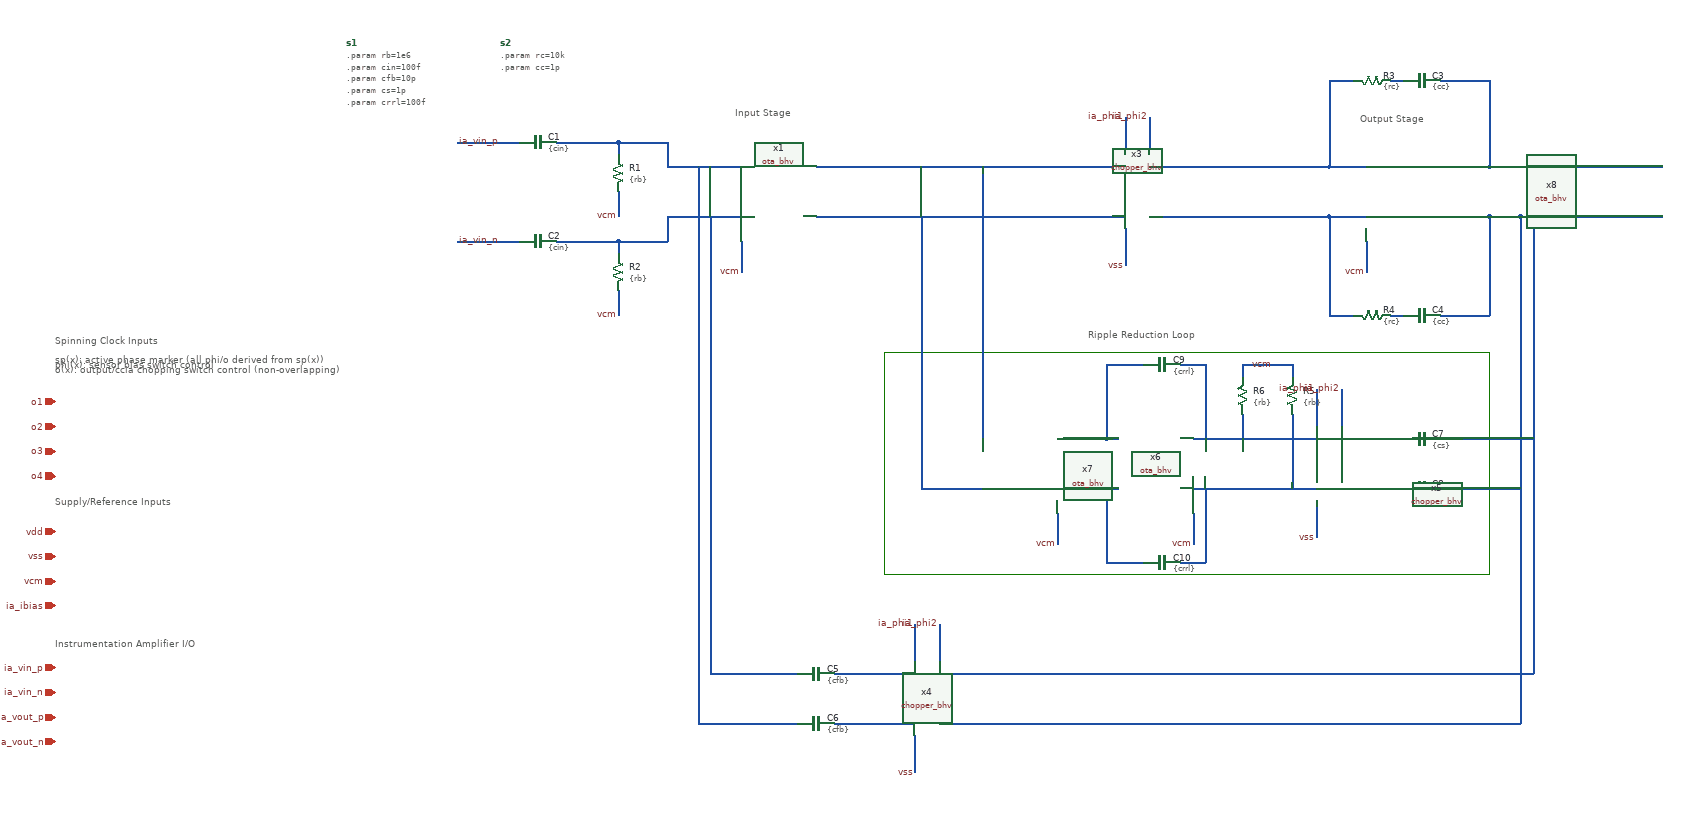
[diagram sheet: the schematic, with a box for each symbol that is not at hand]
v {xschem version=3.4.8RC file_version=1.3}
G {}
K {}
V {}
S {}
F {}
E {}
L 4 1340 -780 2320 -780 {}
L 4 1340 -780 1340 -420 {}
L 4 1340 -420 1900 -420 {}
L 4 1900 -420 2320 -420 {}
L 4 2320 -780 2320 -420 {}
T {Spinning Clock Inputs} 0 -810 0 0 0.4 0.4 {}
T {sp(x): active phase marker (all phi/o derived from sp(x))
phi(x): sensor bias switch control
o(x): output/ccia chopping switch control (non-overlapping)
} 0 -780 0 0 0.2 0.2 {}
T {Supply/Reference Inputs} 0 -550 0 0 0.4 0.4 {}
T {Instrumentation Amplifier I/O} 0 -320 0 0 0.4 0.4 {}
T {Ripple Reduction Loop} 1670 -820 0 0 0.4 0.4 {}
T {Input Stage} 1100 -1180 0 0 0.4 0.4 {}
T {Output Stage} 2110 -1170 0 0 0.4 0.4 {}
N 910 -1040 910 -1020 {lab=vcm}
N 810 -1120 910 -1120 {lab=#net1}
N 910 -1120 910 -1100 {lab=#net1}
N 910 -1020 910 -1000 {lab=vcm}
N 910 -880 910 -860 {lab=vcm}
N 810 -960 910 -960 {lab=#net2}
N 910 -960 910 -940 {lab=#net2}
N 910 -860 910 -840 {lab=vcm}
N 650 -1120 750 -1120 {lab=ia_vin_p}
N 650 -960 750 -960 {lab=ia_vin_n}
N 910 -960 990 -960 {lab=#net2}
N 990 -1000 990 -960 {lab=#net2}
N 990 -1000 1110 -1000 {lab=#net2}
N 910 -1120 990 -1120 {lab=#net1}
N 990 -1120 990 -1080 {lab=#net1}
N 990 -1080 1110 -1080 {lab=#net1}
N 2060 -1080 2120 -1080 {lab=#net3}
N 2060 -1220 2060 -1080 {lab=#net3}
N 2060 -1220 2100 -1220 {lab=#net3}
N 2160 -1220 2180 -1220 {lab=#net4}
N 2240 -1220 2320 -1220 {lab=#net5}
N 2320 -1220 2320 -1080 {lab=#net5}
N 2240 -1080 2320 -1080 {lab=#net5}
N 2240 -1000 2320 -1000 {lab=#net6}
N 2320 -1000 2320 -840 {lab=#net6}
N 2240 -840 2320 -840 {lab=#net6}
N 2160 -840 2180 -840 {lab=#net7}
N 2060 -840 2100 -840 {lab=#net8}
N 2060 -1000 2060 -840 {lab=#net8}
N 1230 -1000 1350 -1000 {lab=#net9}
N 2060 -1000 2120 -1000 {lab=#net8}
N 1230 -1080 1350 -1080 {lab=#net10}
N 1690 -1000 1730 -1000 {lab=#net9}
N 1690 -1080 1730 -1080 {lab=#net10}
N 2000 -1080 2060 -1080 {lab=#net3}
N 2000 -1000 2060 -1000 {lab=#net8}
N 1260 -180 1390 -180 {lab=#net11}
N 1260 -260 1390 -260 {lab=#net12}
N 1430 -180 1800 -180 {lab=#net6}
N 2370 -1000 2370 -570 {lab=#net6}
N 2320 -1000 2370 -1000 {lab=#net6}
N 1070 -260 1200 -260 {lab=#net2}
N 1060 -260 1070 -260 {lab=#net2}
N 1060 -1000 1060 -650 {lab=#net2}
N 1040 -1080 1040 -570 {lab=#net1}
N 1040 -180 1200 -180 {lab=#net1}
N 1110 -960 1110 -910 {lab=vcm}
N 2120 -960 2120 -910 {lab=vcm}
N 1040 -570 1040 -290 {lab=#net1}
N 1060 -650 1060 -370 {lab=#net2}
N 2390 -1080 2390 -370 {lab=#net5}
N 2370 -570 2370 -290 {lab=#net6}
N 2320 -1080 2390 -1080 {lab=#net5}
N 1430 -260 1820 -260 {lab=#net5}
N 1350 -1080 1690 -1080 {lab=#net10}
N 1350 -1000 1690 -1000 {lab=#net9}
N 1770 -1080 2000 -1080 {lab=#net3}
N 1770 -1000 2000 -1000 {lab=#net8}
N 1820 -260 2390 -260 {lab=#net5}
N 1800 -180 2370 -180 {lab=#net6}
N 2240 -640 2390 -640 {lab=#net5}
N 2240 -560 2370 -560 {lab=#net6}
N 2080 -640 2180 -640 {lab=#net13}
N 2080 -560 2180 -560 {lab=#net14}
N 1920 -680 1920 -640 {lab=#net15}
N 1840 -560 2040 -560 {lab=#net16}
N 1840 -640 2040 -640 {lab=#net15}
N 2000 -680 2000 -560 {lab=#net16}
N 1920 -760 1920 -740 {lab=vcm}
N 1920 -760 2000 -760 {lab=vcm}
N 2000 -760 2000 -740 {lab=vcm}
N 1860 -760 1860 -640 {lab=#net15}
N 1820 -760 1860 -760 {lab=#net15}
N 1700 -760 1700 -640 {lab=#net17}
N 1700 -640 1720 -640 {lab=#net17}
N 1700 -760 1760 -760 {lab=#net17}
N 1860 -560 1860 -440 {lab=#net16}
N 1820 -440 1860 -440 {lab=#net16}
N 1700 -560 1700 -440 {lab=#net18}
N 1700 -440 1760 -440 {lab=#net18}
N 1700 -560 1720 -560 {lab=#net18}
N 1620 -640 1700 -640 {lab=#net17}
N 1620 -560 1700 -560 {lab=#net18}
N 1500 -1080 1500 -660 {lab=#net10}
N 1400 -560 1500 -560 {lab=#net9}
N 1400 -1000 1400 -580 {lab=#net9}
N 1400 -580 1400 -560 {lab=#net9}
N 1500 -660 1500 -640 {lab=#net10}
N 2370 -1000 2600 -1000 {lab=#net6}
N 2390 -1080 2600 -1080 {lab=#net5}
N 1730 -1140 1730 -1100 {lab=ia_phi1}
N 1730 -1160 1730 -1140 {lab=ia_phi1}
N 1770 -1140 1770 -1100 {lab=ia_phi2}
N 1770 -1160 1770 -1140 {lab=ia_phi2}
N 1730 -980 1730 -920 {lab=vss}
N 1040 -290 1040 -180 {lab=#net1}
N 1060 -370 1060 -260 {lab=#net2}
N 2370 -290 2370 -180 {lab=#net6}
N 2390 -370 2390 -260 {lab=#net5}
N 1390 -320 1390 -280 {lab=ia_phi1}
N 1390 -340 1390 -320 {lab=ia_phi1}
N 1430 -320 1430 -280 {lab=ia_phi2}
N 1430 -340 1430 -320 {lab=ia_phi2}
N 1390 -160 1390 -100 {lab=vss}
N 2040 -700 2040 -660 {lab=ia_phi1}
N 2040 -720 2040 -700 {lab=ia_phi1}
N 2080 -700 2080 -660 {lab=ia_phi2}
N 2080 -720 2080 -700 {lab=ia_phi2}
N 2040 -540 2040 -480 {lab=vss}
N 1620 -520 1620 -470 {lab=vcm}
N 1840 -520 1840 -470 {lab=vcm}
C {iopin.sym} 0 -700 0 0 {name=p13 lab=o1}
C {iopin.sym} 0 -660 0 0 {name=p14 lab=o2}
C {iopin.sym} 0 -620 0 0 {name=p15 lab=o3}
C {iopin.sym} 0 -580 0 0 {name=p16 lab=o4}
C {iopin.sym} 0 -490 0 0 {name=p20 lab=vdd}
C {iopin.sym} 0 -450 0 0 {name=p21 lab=vss}
C {iopin.sym} 0 -270 0 0 {name=p18 lab=ia_vin_p}
C {iopin.sym} 0 -230 0 0 {name=p19 lab=ia_vin_n}
C {iopin.sym} 0 -410 0 0 {name=p1 lab=vcm}
C {iopin.sym} 0 -370 0 0 {name=p2 lab=ia_ibias}
C {iopin.sym} 0 -190 0 0 {name=p3 lab=ia_vout_p}
C {iopin.sym} 0 -150 0 0 {name=p4 lab=ia_vout_n}
C {title.sym} 160 -40 0 0 {name=l1 author="alang"}
C {capa.sym} 780 -1120 1 0 {name=C1
m=1
value=\{cin\}
footprint=1206
device="ceramic capacitor"}
C {capa.sym} 780 -960 1 0 {name=C2
m=1
value=\{cin\}
footprint=1206
device="ceramic capacitor"}
C {res.sym} 910 -1070 0 0 {name=R1
value=\{rb\}
footprint=1206
device=resistor
m=1}
C {lab_wire.sym} 910 -1000 1 0 {name=p5 sig_type=std_logic lab=vcm}
C {res.sym} 910 -910 0 0 {name=R2
value=\{rb\}
footprint=1206
device=resistor
m=1}
C {lab_wire.sym} 910 -840 1 0 {name=p6 sig_type=std_logic lab=vcm}
C {capa.sym} 2210 -1220 1 0 {name=C3
m=1
value=\{cc\}
footprint=1206
device="ceramic capacitor"}
C {res.sym} 2130 -1220 1 0 {name=R3
value=\{rc\}
footprint=1206
device=resistor
m=1}
C {capa.sym} 2210 -840 1 0 {name=C4
m=1
value=\{cc\}
footprint=1206
device="ceramic capacitor"}
C {res.sym} 2130 -840 1 0 {name=R4
value=\{rc\}
footprint=1206
device=resistor
m=1}
C {chopper_bhv/chopper_bhv.sym} 1730 -980 0 0 {name=x3}
C {chopper_bhv/chopper_bhv.sym} 1390 -160 0 0 {name=x4}
C {capa.sym} 1230 -260 1 0 {name=C5
m=1
value=\{cfb\}
footprint=1206
device="ceramic capacitor"}
C {capa.sym} 1230 -180 1 0 {name=C6
m=1
value=\{cfb\}
footprint=1206
device="ceramic capacitor"}
C {lab_wire.sym} 1110 -910 1 0 {name=p7 sig_type=std_logic lab=vcm}
C {lab_wire.sym} 2120 -910 1 0 {name=p8 sig_type=std_logic lab=vcm}
C {capa.sym} 2210 -640 1 0 {name=C7
m=1
value=\{cs\}
footprint=1206
device="ceramic capacitor"}
C {capa.sym} 2210 -560 1 0 {name=C8
m=1
value=\{cs\}
footprint=1206
device="ceramic capacitor"}
C {chopper_bhv/chopper_bhv.sym} 2040 -540 0 0 {name=x5}
C {res.sym} 2000 -710 2 0 {name=R5
value=\{rb\}
footprint=1206
device=resistor
m=1}
C {res.sym} 1920 -710 2 0 {name=R6
value=\{rb\}
footprint=1206
device=resistor
m=1}
C {lab_wire.sym} 1970 -760 0 0 {name=p9 sig_type=std_logic lab=vcm}
C {ota_bhv/ota_bhv.sym} 1840 -520 0 1 {name=x6 rout=1e6 dc_gain=100}
C {capa.sym} 1790 -760 1 0 {name=C9
m=1
value=\{crrl\}
footprint=1206
device="ceramic capacitor"}
C {capa.sym} 1790 -440 1 1 {name=C10
m=1
value=\{crrl\}
footprint=1206
device="ceramic capacitor"}
C {ota_bhv/ota_bhv.sym} 1620 -520 0 1 {name=x7 rout=1e6 dc_gain=100}
C {lab_wire.sym} 1730 -1160 3 0 {name=p10 sig_type=std_logic lab=ia_phi1}
C {lab_wire.sym} 1770 -1160 3 0 {name=p11 sig_type=std_logic lab=ia_phi2}
C {lab_wire.sym} 1730 -920 3 1 {name=p12 sig_type=std_logic lab=vss}
C {lab_wire.sym} 1390 -340 3 0 {name=p17 sig_type=std_logic lab=ia_phi1}
C {lab_wire.sym} 1430 -340 3 0 {name=p22 sig_type=std_logic lab=ia_phi2}
C {lab_wire.sym} 1390 -100 3 1 {name=p23 sig_type=std_logic lab=vss}
C {lab_wire.sym} 2040 -720 3 0 {name=p24 sig_type=std_logic lab=ia_phi1}
C {lab_wire.sym} 2080 -720 3 0 {name=p25 sig_type=std_logic lab=ia_phi2}
C {lab_wire.sym} 2040 -480 3 1 {name=p26 sig_type=std_logic lab=vss}
C {code_shown.sym} 470 -1280 0 0 {name=s1 only_toplevel=false value=".param rb=1e6
.param cin=100f
.param cfb=10p
.param cs=1p
.param crrl=100f"}
C {ota_bhv/ota_bhv.sym} 1110 -960 0 0 {name=x1 rout=10e6 dc_gain=5000}
C {ota_bhv/ota_bhv.sym} 2120 -960 0 0 {name=x8 rout=100e3 dc_gain=100}
C {code_shown.sym} 720 -1280 0 0 {name=s2 only_toplevel=false value=".param rc=10k
.param cc=1p"}
C {lab_wire.sym} 650 -1120 0 1 {name=p27 sig_type=std_logic lab=ia_vin_p}
C {lab_wire.sym} 650 -960 0 1 {name=p28 sig_type=std_logic lab=ia_vin_n}
C {lab_wire.sym} 1620 -470 1 0 {name=p29 sig_type=std_logic lab=vcm}
C {lab_wire.sym} 1840 -470 1 0 {name=p30 sig_type=std_logic lab=vcm}
